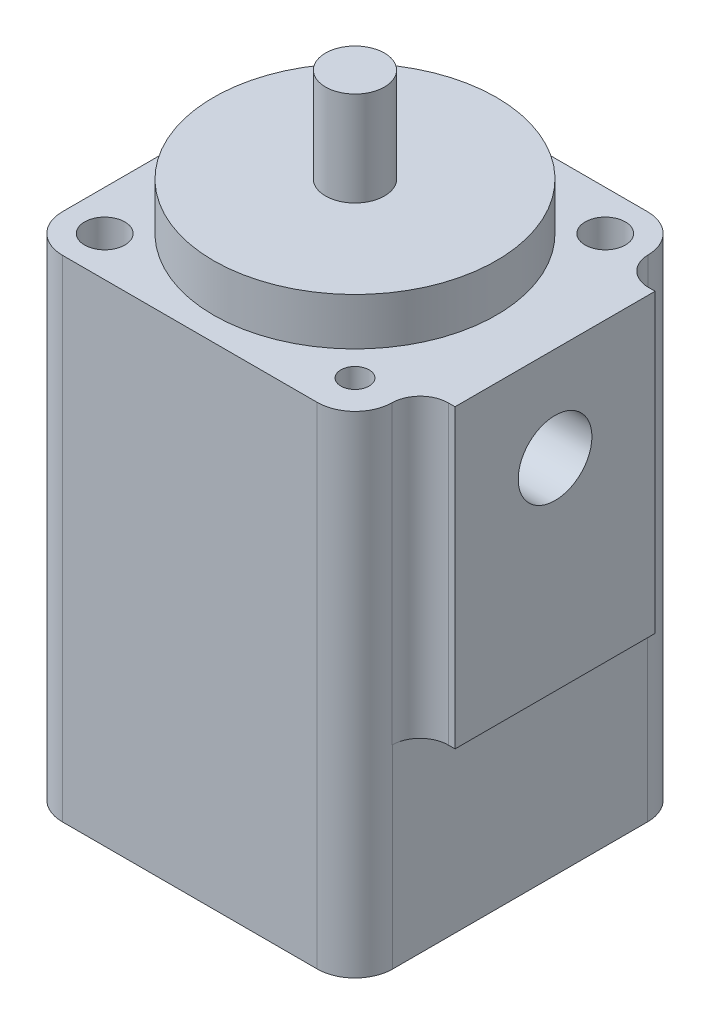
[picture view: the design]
ISO-10303-21;
HEADER;
FILE_DESCRIPTION(('STEP AP214'),'2;1');
FILE_NAME('part.step','',(''),(''),'','','');
FILE_SCHEMA(('AUTOMOTIVE_DESIGN { 1 0 10303 214 1 1 1 1 }'));
ENDSEC;
DATA;
#1=APPLICATION_CONTEXT('core data for automotive mechanical design processes');
#2=APPLICATION_PROTOCOL_DEFINITION('international standard','automotive_design',2000,#1);
#3=PRODUCT_CONTEXT('',#1,'mechanical');
#4=PRODUCT('Part','Part','',(#3));
#5=PRODUCT_RELATED_PRODUCT_CATEGORY('part','',(#4));
#6=PRODUCT_DEFINITION_FORMATION('','',#4);
#7=PRODUCT_DEFINITION_CONTEXT('part definition',#1,'design');
#8=PRODUCT_DEFINITION('design','',#6,#7);
#9=PRODUCT_DEFINITION_SHAPE('','',#8);
#10=(LENGTH_UNIT() NAMED_UNIT(*) SI_UNIT(.MILLI.,.METRE.));
#11=(NAMED_UNIT(*) PLANE_ANGLE_UNIT() SI_UNIT($,.RADIAN.));
#12=(NAMED_UNIT(*) SI_UNIT($,.STERADIAN.) SOLID_ANGLE_UNIT());
#13=UNCERTAINTY_MEASURE_WITH_UNIT(LENGTH_MEASURE(1.E-05),#10,'distance_accuracy_value','');
#14=(GEOMETRIC_REPRESENTATION_CONTEXT(3) GLOBAL_UNCERTAINTY_ASSIGNED_CONTEXT((#13)) GLOBAL_UNIT_ASSIGNED_CONTEXT((#10,
#11,#12)) REPRESENTATION_CONTEXT('',''));
#15=CARTESIAN_POINT('',(0.,0.,0.));
#16=DIRECTION('',(0.,0.,1.));
#17=DIRECTION('',(1.,0.,0.));
#18=AXIS2_PLACEMENT_3D('',#15,#16,#17);
#19=CARTESIAN_POINT('',(0.,85.09,0.));
#20=DIRECTION('',(0.,-1.,0.));
#21=DIRECTION('',(0.,0.,-1.));
#22=AXIS2_PLACEMENT_3D('',#19,#20,#21);
#23=PLANE('',#22);
#24=CARTESIAN_POINT('',(0.,85.09,0.));
#25=DIRECTION('',(0.,-1.,0.));
#26=DIRECTION('',(0.,0.,-1.));
#27=AXIS2_PLACEMENT_3D('',#24,#25,#26);
#28=CIRCLE('',#27,3.9624);
#29=CARTESIAN_POINT('',(0.,85.09,-3.9624));
#30=VERTEX_POINT('',#29);
#31=EDGE_CURVE('E13',#30,#30,#28,.T.);
#32=ORIENTED_EDGE('',*,*,#31,.F.);
#33=EDGE_LOOP('',(#32));
#34=FACE_BOUND('',#33,.T.);
#35=ADVANCED_FACE('F58',(#34),#23,.F.);
#36=CARTESIAN_POINT('',(0.,0.,0.));
#37=DIRECTION('',(0.,-1.,0.));
#38=DIRECTION('',(0.,0.,-1.));
#39=AXIS2_PLACEMENT_3D('',#36,#37,#38);
#40=CYLINDRICAL_SURFACE('',#39,3.9624);
#41=CARTESIAN_POINT('',(0.,46.99,0.));
#42=DIRECTION('',(0.,-1.,0.));
#43=DIRECTION('',(0.,0.,-1.));
#44=AXIS2_PLACEMENT_3D('',#41,#42,#43);
#45=CIRCLE('',#44,3.9624);
#46=CARTESIAN_POINT('',(0.,46.99,-3.9624));
#47=VERTEX_POINT('',#46);
#48=EDGE_CURVE('E64',#47,#47,#45,.T.);
#49=ORIENTED_EDGE('',*,*,#48,.F.);
#50=EDGE_LOOP('',(#49));
#51=FACE_BOUND('',#50,.T.);
#52=ORIENTED_EDGE('',*,*,#31,.T.);
#53=EDGE_LOOP('',(#52));
#54=FACE_BOUND('',#53,.T.);
#55=ADVANCED_FACE('F72',(#51,#54),#40,.T.);
#56=CARTESIAN_POINT('',(0.,46.99,0.));
#57=DIRECTION('',(0.,1.,0.));
#58=DIRECTION('',(0.,0.,1.));
#59=AXIS2_PLACEMENT_3D('',#56,#57,#58);
#60=PLANE('',#59);
#61=ORIENTED_EDGE('',*,*,#48,.T.);
#62=EDGE_LOOP('',(#61));
#63=FACE_BOUND('',#62,.T.);
#64=ADVANCED_FACE('F70',(#63),#60,.F.);
#65=CLOSED_SHELL('',(#35,#55,#64));
#66=MANIFOLD_SOLID_BREP('B2',#65);
#67=CARTESIAN_POINT('',(22.225,66.04,-22.225));
#68=DIRECTION('',(0.,-1.,0.));
#69=DIRECTION('',(0.,0.,-1.));
#70=AXIS2_PLACEMENT_3D('',#67,#68,#69);
#71=PLANE('',#70);
#72=CARTESIAN_POINT('',(16.8402,66.04,-16.8402));
#73=DIRECTION('',(0.,1.,0.));
#74=DIRECTION('',(0.,0.,1.));
#75=AXIS2_PLACEMENT_3D('',#72,#73,#74);
#76=CIRCLE('',#75,2.70509999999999);
#77=CARTESIAN_POINT('',(16.8402,66.04,-14.1351));
#78=VERTEX_POINT('',#77);
#79=EDGE_CURVE('E302',#78,#78,#76,.T.);
#80=ORIENTED_EDGE('',*,*,#79,.F.);
#81=EDGE_LOOP('',(#80));
#82=FACE_BOUND('',#81,.T.);
#83=CARTESIAN_POINT('',(-16.8402,66.04,-16.8402));
#84=DIRECTION('',(0.,1.,0.));
#85=DIRECTION('',(0.,0.,1.));
#86=AXIS2_PLACEMENT_3D('',#83,#84,#85);
#87=CIRCLE('',#86,1.89864999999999);
#88=CARTESIAN_POINT('',(-16.8402,66.04,-14.94155));
#89=VERTEX_POINT('',#88);
#90=EDGE_CURVE('E314',#89,#89,#87,.T.);
#91=ORIENTED_EDGE('',*,*,#90,.F.);
#92=EDGE_LOOP('',(#91));
#93=FACE_BOUND('',#92,.T.);
#94=DIRECTION('',(-1.,0.,0.));
#95=VECTOR('',#94,1.);
#96=CARTESIAN_POINT('',(-22.225,66.04,-22.225));
#97=LINE('',#96,#95);
#98=CARTESIAN_POINT('',(17.145,66.04,-22.225));
#99=VERTEX_POINT('',#98);
#100=CARTESIAN_POINT('',(-17.145,66.04,-22.225));
#101=VERTEX_POINT('',#100);
#102=EDGE_CURVE('E364',#99,#101,#97,.T.);
#103=ORIENTED_EDGE('',*,*,#102,.T.);
#104=CARTESIAN_POINT('',(-17.145,66.04,-17.145));
#105=DIRECTION('',(0.,-1.,0.));
#106=DIRECTION('',(0.,0.,-1.));
#107=AXIS2_PLACEMENT_3D('',#104,#105,#106);
#108=CIRCLE('',#107,5.08);
#109=CARTESIAN_POINT('',(-22.225,66.04,-17.145));
#110=VERTEX_POINT('',#109);
#111=EDGE_CURVE('E412',#101,#110,#108,.F.);
#112=ORIENTED_EDGE('',*,*,#111,.T.);
#113=DIRECTION('',(0.,0.,1.));
#114=VECTOR('',#113,1.);
#115=CARTESIAN_POINT('',(-22.225,66.04,22.225));
#116=LINE('',#115,#114);
#117=CARTESIAN_POINT('',(-22.225,66.04,17.145));
#118=VERTEX_POINT('',#117);
#119=EDGE_CURVE('E367',#110,#118,#116,.T.);
#120=ORIENTED_EDGE('',*,*,#119,.T.);
#121=CARTESIAN_POINT('',(-17.145,66.04,17.145));
#122=DIRECTION('',(0.,-1.,0.));
#123=DIRECTION('',(0.,0.,-1.));
#124=AXIS2_PLACEMENT_3D('',#121,#122,#123);
#125=CIRCLE('',#124,5.08);
#126=CARTESIAN_POINT('',(-17.145,66.04,22.225));
#127=VERTEX_POINT('',#126);
#128=EDGE_CURVE('E410',#118,#127,#125,.F.);
#129=ORIENTED_EDGE('',*,*,#128,.T.);
#130=DIRECTION('',(1.,0.,0.));
#131=VECTOR('',#130,1.);
#132=CARTESIAN_POINT('',(-22.225,66.04,22.225));
#133=LINE('',#132,#131);
#134=CARTESIAN_POINT('',(17.145,66.04,22.225));
#135=VERTEX_POINT('',#134);
#136=EDGE_CURVE('E371',#127,#135,#133,.T.);
#137=ORIENTED_EDGE('',*,*,#136,.T.);
#138=CARTESIAN_POINT('',(17.145,66.04,17.145));
#139=DIRECTION('',(0.,-1.,0.));
#140=DIRECTION('',(0.,0.,-1.));
#141=AXIS2_PLACEMENT_3D('',#138,#139,#140);
#142=CIRCLE('',#141,5.08);
#143=CARTESIAN_POINT('',(22.2244816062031,66.04,17.2175714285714));
#144=VERTEX_POINT('',#143);
#145=EDGE_CURVE('E405',#135,#144,#142,.F.);
#146=ORIENTED_EDGE('',*,*,#145,.T.);
#147=CARTESIAN_POINT('',(26.0340928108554,66.04,17.272));
#148=DIRECTION('',(0.,-1.,0.));
#149=DIRECTION('',(0.,0.,-1.));
#150=AXIS2_PLACEMENT_3D('',#147,#148,#149);
#151=CIRCLE('',#150,3.81);
#152=CARTESIAN_POINT('',(26.0340928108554,66.04,13.462));
#153=VERTEX_POINT('',#152);
#154=EDGE_CURVE('E441',#144,#153,#151,.T.);
#155=ORIENTED_EDGE('',*,*,#154,.T.);
#156=DIRECTION('',(1.,0.,0.));
#157=VECTOR('',#156,1.);
#158=CARTESIAN_POINT('',(26.924,66.04,13.462));
#159=LINE('',#158,#157);
#160=CARTESIAN_POINT('',(26.924,66.04,13.462));
#161=VERTEX_POINT('',#160);
#162=EDGE_CURVE('E343',#153,#161,#159,.T.);
#163=ORIENTED_EDGE('',*,*,#162,.T.);
#164=DIRECTION('',(0.,0.,-1.));
#165=VECTOR('',#164,1.);
#166=CARTESIAN_POINT('',(26.924,66.04,-13.462));
#167=LINE('',#166,#165);
#168=CARTESIAN_POINT('',(26.924,66.04,-13.462));
#169=VERTEX_POINT('',#168);
#170=EDGE_CURVE('E345',#161,#169,#167,.T.);
#171=ORIENTED_EDGE('',*,*,#170,.T.);
#172=DIRECTION('',(-1.,0.,0.));
#173=VECTOR('',#172,1.);
#174=CARTESIAN_POINT('',(22.225,66.04,-13.462));
#175=LINE('',#174,#173);
#176=CARTESIAN_POINT('',(26.0340928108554,66.04,-13.462));
#177=VERTEX_POINT('',#176);
#178=EDGE_CURVE('E334',#169,#177,#175,.T.);
#179=ORIENTED_EDGE('',*,*,#178,.T.);
#180=CARTESIAN_POINT('',(26.0340928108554,66.04,-17.272));
#181=DIRECTION('',(0.,-1.,0.));
#182=DIRECTION('',(0.,0.,-1.));
#183=AXIS2_PLACEMENT_3D('',#180,#181,#182);
#184=CIRCLE('',#183,3.81);
#185=CARTESIAN_POINT('',(22.2244816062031,66.04,-17.2175714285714));
#186=VERTEX_POINT('',#185);
#187=EDGE_CURVE('E445',#177,#186,#184,.T.);
#188=ORIENTED_EDGE('',*,*,#187,.T.);
#189=CARTESIAN_POINT('',(17.145,66.04,-17.145));
#190=DIRECTION('',(0.,-1.,0.));
#191=DIRECTION('',(0.,0.,-1.));
#192=AXIS2_PLACEMENT_3D('',#189,#190,#191);
#193=CIRCLE('',#192,5.08);
#194=EDGE_CURVE('E408',#186,#99,#193,.F.);
#195=ORIENTED_EDGE('',*,*,#194,.T.);
#196=EDGE_LOOP('',(#103,#112,#120,#129,#137,#146,#155,#163,#171,#179,#188,#195));
#197=FACE_BOUND('',#196,.T.);
#198=CARTESIAN_POINT('',(0.,66.04,0.));
#199=DIRECTION('',(0.,-1.,0.));
#200=DIRECTION('',(0.,0.,-1.));
#201=AXIS2_PLACEMENT_3D('',#198,#199,#200);
#202=CIRCLE('',#201,19.0373);
#203=CARTESIAN_POINT('',(0.,66.04,-19.0373));
#204=VERTEX_POINT('',#203);
#205=EDGE_CURVE('E374',#204,#204,#202,.F.);
#206=ORIENTED_EDGE('',*,*,#205,.F.);
#207=EDGE_LOOP('',(#206));
#208=FACE_BOUND('',#207,.T.);
#209=CARTESIAN_POINT('',(16.8402,66.04,16.8402));
#210=DIRECTION('',(0.,1.,0.));
#211=DIRECTION('',(0.,0.,1.));
#212=AXIS2_PLACEMENT_3D('',#209,#210,#211);
#213=CIRCLE('',#212,1.89864999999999);
#214=CARTESIAN_POINT('',(16.8402,66.04,18.73885));
#215=VERTEX_POINT('',#214);
#216=EDGE_CURVE('E320',#215,#215,#213,.T.);
#217=ORIENTED_EDGE('',*,*,#216,.F.);
#218=EDGE_LOOP('',(#217));
#219=FACE_BOUND('',#218,.T.);
#220=CARTESIAN_POINT('',(-16.8402,66.04,16.8402));
#221=DIRECTION('',(0.,1.,0.));
#222=DIRECTION('',(0.,0.,1.));
#223=AXIS2_PLACEMENT_3D('',#220,#221,#222);
#224=CIRCLE('',#223,2.70509999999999);
#225=CARTESIAN_POINT('',(-16.8402,66.04,19.5453));
#226=VERTEX_POINT('',#225);
#227=EDGE_CURVE('E308',#226,#226,#224,.T.);
#228=ORIENTED_EDGE('',*,*,#227,.F.);
#229=EDGE_LOOP('',(#228));
#230=FACE_BOUND('',#229,.T.);
#231=ADVANCED_FACE('F104',(#82,#93,#197,#208,#219,#230),#71,.F.);
#232=CARTESIAN_POINT('',(22.225,0.,-22.225));
#233=DIRECTION('',(0.,-1.,0.));
#234=DIRECTION('',(0.,0.,-1.));
#235=AXIS2_PLACEMENT_3D('',#232,#233,#234);
#236=PLANE('',#235);
#237=CARTESIAN_POINT('',(0.,0.,-9.52500000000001));
#238=DIRECTION('',(0.,-1.,0.));
#239=DIRECTION('',(0.,0.,-1.));
#240=AXIS2_PLACEMENT_3D('',#237,#238,#239);
#241=CIRCLE('',#240,10.5);
#242=CARTESIAN_POINT('',(-4.41863949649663,0.,0.));
#243=VERTEX_POINT('',#242);
#244=CARTESIAN_POINT('',(4.41863949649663,0.,0.));
#245=VERTEX_POINT('',#244);
#246=EDGE_CURVE('E268',#243,#245,#241,.T.);
#247=ORIENTED_EDGE('',*,*,#246,.F.);
#248=CARTESIAN_POINT('',(0.,0.,9.52500000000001));
#249=DIRECTION('',(0.,-1.,0.));
#250=DIRECTION('',(0.,0.,-1.));
#251=AXIS2_PLACEMENT_3D('',#248,#249,#250);
#252=CIRCLE('',#251,10.5);
#253=EDGE_CURVE('E299',#245,#243,#252,.T.);
#254=ORIENTED_EDGE('',*,*,#253,.F.);
#255=EDGE_LOOP('',(#247,#254));
#256=FACE_BOUND('',#255,.T.);
#257=CARTESIAN_POINT('',(16.8402,0.,-16.8402));
#258=DIRECTION('',(0.,1.,0.));
#259=DIRECTION('',(0.,0.,1.));
#260=AXIS2_PLACEMENT_3D('',#257,#258,#259);
#261=CIRCLE('',#260,2.70509999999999);
#262=CARTESIAN_POINT('',(16.8402,0.,-14.1351));
#263=VERTEX_POINT('',#262);
#264=EDGE_CURVE('E305',#263,#263,#261,.T.);
#265=ORIENTED_EDGE('',*,*,#264,.T.);
#266=EDGE_LOOP('',(#265));
#267=FACE_BOUND('',#266,.T.);
#268=CARTESIAN_POINT('',(-16.8402,0.,16.8402));
#269=DIRECTION('',(0.,1.,0.));
#270=DIRECTION('',(0.,0.,1.));
#271=AXIS2_PLACEMENT_3D('',#268,#269,#270);
#272=CIRCLE('',#271,2.70509999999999);
#273=CARTESIAN_POINT('',(-16.8402,0.,19.5453));
#274=VERTEX_POINT('',#273);
#275=EDGE_CURVE('E311',#274,#274,#272,.T.);
#276=ORIENTED_EDGE('',*,*,#275,.T.);
#277=EDGE_LOOP('',(#276));
#278=FACE_BOUND('',#277,.T.);
#279=CARTESIAN_POINT('',(-16.8402,0.,-16.8402));
#280=DIRECTION('',(0.,1.,0.));
#281=DIRECTION('',(0.,0.,1.));
#282=AXIS2_PLACEMENT_3D('',#279,#280,#281);
#283=CIRCLE('',#282,1.89864999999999);
#284=CARTESIAN_POINT('',(-16.8402,0.,-14.94155));
#285=VERTEX_POINT('',#284);
#286=EDGE_CURVE('E317',#285,#285,#283,.T.);
#287=ORIENTED_EDGE('',*,*,#286,.T.);
#288=EDGE_LOOP('',(#287));
#289=FACE_BOUND('',#288,.T.);
#290=DIRECTION('',(0.,0.,1.));
#291=VECTOR('',#290,1.);
#292=CARTESIAN_POINT('',(-22.225,0.,22.225));
#293=LINE('',#292,#291);
#294=CARTESIAN_POINT('',(-22.225,0.,-17.145));
#295=VERTEX_POINT('',#294);
#296=CARTESIAN_POINT('',(-22.225,0.,17.145));
#297=VERTEX_POINT('',#296);
#298=EDGE_CURVE('E380',#295,#297,#293,.T.);
#299=ORIENTED_EDGE('',*,*,#298,.F.);
#300=CARTESIAN_POINT('',(-17.145,0.,-17.145));
#301=DIRECTION('',(0.,-1.,0.));
#302=DIRECTION('',(0.,0.,-1.));
#303=AXIS2_PLACEMENT_3D('',#300,#301,#302);
#304=CIRCLE('',#303,5.08);
#305=CARTESIAN_POINT('',(-17.145,0.,-22.225));
#306=VERTEX_POINT('',#305);
#307=EDGE_CURVE('E398',#295,#306,#304,.T.);
#308=ORIENTED_EDGE('',*,*,#307,.T.);
#309=DIRECTION('',(-1.,0.,0.));
#310=VECTOR('',#309,1.);
#311=CARTESIAN_POINT('',(-22.225,0.,-22.225));
#312=LINE('',#311,#310);
#313=CARTESIAN_POINT('',(17.145,0.,-22.225));
#314=VERTEX_POINT('',#313);
#315=EDGE_CURVE('E377',#314,#306,#312,.T.);
#316=ORIENTED_EDGE('',*,*,#315,.F.);
#317=CARTESIAN_POINT('',(17.145,0.,-17.145));
#318=DIRECTION('',(0.,-1.,0.));
#319=DIRECTION('',(0.,0.,-1.));
#320=AXIS2_PLACEMENT_3D('',#317,#318,#319);
#321=CIRCLE('',#320,5.08);
#322=CARTESIAN_POINT('',(22.225,0.,-17.145));
#323=VERTEX_POINT('',#322);
#324=EDGE_CURVE('E394',#314,#323,#321,.T.);
#325=ORIENTED_EDGE('',*,*,#324,.T.);
#326=DIRECTION('',(0.,0.,-1.));
#327=VECTOR('',#326,1.);
#328=CARTESIAN_POINT('',(22.225,0.,22.225));
#329=LINE('',#328,#327);
#330=CARTESIAN_POINT('',(22.225,0.,17.145));
#331=VERTEX_POINT('',#330);
#332=EDGE_CURVE('E363',#331,#323,#329,.T.);
#333=ORIENTED_EDGE('',*,*,#332,.F.);
#334=CARTESIAN_POINT('',(17.145,0.,17.145));
#335=DIRECTION('',(0.,-1.,0.));
#336=DIRECTION('',(0.,0.,-1.));
#337=AXIS2_PLACEMENT_3D('',#334,#335,#336);
#338=CIRCLE('',#337,5.08);
#339=CARTESIAN_POINT('',(17.145,0.,22.225));
#340=VERTEX_POINT('',#339);
#341=EDGE_CURVE('E392',#331,#340,#338,.T.);
#342=ORIENTED_EDGE('',*,*,#341,.T.);
#343=DIRECTION('',(1.,0.,0.));
#344=VECTOR('',#343,1.);
#345=CARTESIAN_POINT('',(-22.225,0.,22.225));
#346=LINE('',#345,#344);
#347=CARTESIAN_POINT('',(-17.145,0.,22.225));
#348=VERTEX_POINT('',#347);
#349=EDGE_CURVE('E368',#348,#340,#346,.T.);
#350=ORIENTED_EDGE('',*,*,#349,.F.);
#351=CARTESIAN_POINT('',(-17.145,0.,17.145));
#352=DIRECTION('',(0.,-1.,0.));
#353=DIRECTION('',(0.,0.,-1.));
#354=AXIS2_PLACEMENT_3D('',#351,#352,#353);
#355=CIRCLE('',#354,5.08);
#356=EDGE_CURVE('E396',#348,#297,#355,.T.);
#357=ORIENTED_EDGE('',*,*,#356,.T.);
#358=EDGE_LOOP('',(#299,#308,#316,#325,#333,#342,#350,#357));
#359=FACE_BOUND('',#358,.T.);
#360=CARTESIAN_POINT('',(16.8402,0.,16.8402));
#361=DIRECTION('',(0.,1.,0.));
#362=DIRECTION('',(0.,0.,1.));
#363=AXIS2_PLACEMENT_3D('',#360,#361,#362);
#364=CIRCLE('',#363,1.89864999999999);
#365=CARTESIAN_POINT('',(16.8402,0.,18.73885));
#366=VERTEX_POINT('',#365);
#367=EDGE_CURVE('E323',#366,#366,#364,.T.);
#368=ORIENTED_EDGE('',*,*,#367,.T.);
#369=EDGE_LOOP('',(#368));
#370=FACE_BOUND('',#369,.T.);
#371=ADVANCED_FACE('F505',(#256,#267,#278,#289,#359,#370),#236,.T.);
#372=CARTESIAN_POINT('',(22.225,66.04,22.225));
#373=DIRECTION('',(-1.,0.,0.));
#374=DIRECTION('',(0.,0.,1.));
#375=AXIS2_PLACEMENT_3D('',#372,#373,#374);
#376=PLANE('',#375);
#377=DIRECTION('',(0.,0.,1.));
#378=VECTOR('',#377,1.);
#379=CARTESIAN_POINT('',(22.225,26.162,-13.462));
#380=LINE('',#379,#378);
#381=CARTESIAN_POINT('',(22.225,26.162,-17.145));
#382=VERTEX_POINT('',#381);
#383=CARTESIAN_POINT('',(22.225,26.162,17.145));
#384=VERTEX_POINT('',#383);
#385=EDGE_CURVE('E331',#382,#384,#380,.T.);
#386=ORIENTED_EDGE('',*,*,#385,.T.);
#387=DIRECTION('',(0.,-1.,0.));
#388=VECTOR('',#387,1.);
#389=CARTESIAN_POINT('',(22.225,66.04,17.145));
#390=LINE('',#389,#388);
#391=EDGE_CURVE('E419',#384,#331,#390,.T.);
#392=ORIENTED_EDGE('',*,*,#391,.T.);
#393=ORIENTED_EDGE('',*,*,#332,.T.);
#394=DIRECTION('',(0.,-1.,0.));
#395=VECTOR('',#394,1.);
#396=CARTESIAN_POINT('',(22.225,66.04,-17.145));
#397=LINE('',#396,#395);
#398=EDGE_CURVE('E421',#323,#382,#397,.F.);
#399=ORIENTED_EDGE('',*,*,#398,.T.);
#400=EDGE_LOOP('',(#386,#392,#393,#399));
#401=FACE_BOUND('',#400,.T.);
#402=ADVANCED_FACE('F511',(#401),#376,.F.);
#403=CARTESIAN_POINT('',(-22.225,66.04,-22.225));
#404=DIRECTION('',(0.,0.,1.));
#405=DIRECTION('',(1.,0.,0.));
#406=AXIS2_PLACEMENT_3D('',#403,#404,#405);
#407=PLANE('',#406);
#408=ORIENTED_EDGE('',*,*,#315,.T.);
#409=DIRECTION('',(0.,-1.,0.));
#410=VECTOR('',#409,1.);
#411=CARTESIAN_POINT('',(-17.145,66.04,-22.225));
#412=LINE('',#411,#410);
#413=EDGE_CURVE('E403',#306,#101,#412,.F.);
#414=ORIENTED_EDGE('',*,*,#413,.T.);
#415=ORIENTED_EDGE('',*,*,#102,.F.);
#416=DIRECTION('',(0.,-1.,0.));
#417=VECTOR('',#416,1.);
#418=CARTESIAN_POINT('',(17.145,66.04,-22.225));
#419=LINE('',#418,#417);
#420=EDGE_CURVE('E400',#99,#314,#419,.T.);
#421=ORIENTED_EDGE('',*,*,#420,.T.);
#422=EDGE_LOOP('',(#408,#414,#415,#421));
#423=FACE_BOUND('',#422,.T.);
#424=ADVANCED_FACE('F526',(#423),#407,.F.);
#425=CARTESIAN_POINT('',(-22.225,66.04,22.225));
#426=DIRECTION('',(1.,0.,0.));
#427=DIRECTION('',(0.,0.,-1.));
#428=AXIS2_PLACEMENT_3D('',#425,#426,#427);
#429=PLANE('',#428);
#430=ORIENTED_EDGE('',*,*,#119,.F.);
#431=DIRECTION('',(0.,-1.,0.));
#432=VECTOR('',#431,1.);
#433=CARTESIAN_POINT('',(-22.225,66.04,-17.145));
#434=LINE('',#433,#432);
#435=EDGE_CURVE('E389',#110,#295,#434,.T.);
#436=ORIENTED_EDGE('',*,*,#435,.T.);
#437=ORIENTED_EDGE('',*,*,#298,.T.);
#438=DIRECTION('',(0.,-1.,0.));
#439=VECTOR('',#438,1.);
#440=CARTESIAN_POINT('',(-22.225,66.04,17.145));
#441=LINE('',#440,#439);
#442=EDGE_CURVE('E387',#297,#118,#441,.F.);
#443=ORIENTED_EDGE('',*,*,#442,.T.);
#444=EDGE_LOOP('',(#430,#436,#437,#443));
#445=FACE_BOUND('',#444,.T.);
#446=ADVANCED_FACE('F522',(#445),#429,.F.);
#447=CARTESIAN_POINT('',(-22.225,66.04,22.225));
#448=DIRECTION('',(0.,0.,-1.));
#449=DIRECTION('',(-1.,0.,0.));
#450=AXIS2_PLACEMENT_3D('',#447,#448,#449);
#451=PLANE('',#450);
#452=ORIENTED_EDGE('',*,*,#136,.F.);
#453=DIRECTION('',(0.,-1.,0.));
#454=VECTOR('',#453,1.);
#455=CARTESIAN_POINT('',(-17.145,66.04,22.225));
#456=LINE('',#455,#454);
#457=EDGE_CURVE('E416',#127,#348,#456,.T.);
#458=ORIENTED_EDGE('',*,*,#457,.T.);
#459=ORIENTED_EDGE('',*,*,#349,.T.);
#460=DIRECTION('',(0.,-1.,0.));
#461=VECTOR('',#460,1.);
#462=CARTESIAN_POINT('',(17.145,66.04,22.225));
#463=LINE('',#462,#461);
#464=EDGE_CURVE('E414',#340,#135,#463,.F.);
#465=ORIENTED_EDGE('',*,*,#464,.T.);
#466=EDGE_LOOP('',(#452,#458,#459,#465));
#467=FACE_BOUND('',#466,.T.);
#468=ADVANCED_FACE('F519',(#467),#451,.F.);
#469=CARTESIAN_POINT('',(0.,72.39,0.));
#470=DIRECTION('',(0.,-1.,0.));
#471=DIRECTION('',(0.,0.,-1.));
#472=AXIS2_PLACEMENT_3D('',#469,#470,#471);
#473=CYLINDRICAL_SURFACE('',#472,19.0373);
#474=CARTESIAN_POINT('',(0.,72.39,0.));
#475=DIRECTION('',(0.,1.,0.));
#476=DIRECTION('',(0.,0.,1.));
#477=AXIS2_PLACEMENT_3D('',#474,#475,#476);
#478=CIRCLE('',#477,19.0373);
#479=CARTESIAN_POINT('',(0.,72.39,19.0373));
#480=VERTEX_POINT('',#479);
#481=EDGE_CURVE('E358',#480,#480,#478,.T.);
#482=ORIENTED_EDGE('',*,*,#481,.F.);
#483=EDGE_LOOP('',(#482));
#484=FACE_BOUND('',#483,.T.);
#485=ORIENTED_EDGE('',*,*,#205,.T.);
#486=EDGE_LOOP('',(#485));
#487=FACE_BOUND('',#486,.T.);
#488=ADVANCED_FACE('F517',(#484,#487),#473,.T.);
#489=CARTESIAN_POINT('',(0.,72.39,0.));
#490=DIRECTION('',(0.,1.,0.));
#491=DIRECTION('',(0.,0.,1.));
#492=AXIS2_PLACEMENT_3D('',#489,#490,#491);
#493=PLANE('',#492);
#494=CARTESIAN_POINT('',(0.,72.39,0.));
#495=DIRECTION('',(0.,1.,0.));
#496=DIRECTION('',(0.,0.,1.));
#497=AXIS2_PLACEMENT_3D('',#494,#495,#496);
#498=CIRCLE('',#497,3.96875);
#499=CARTESIAN_POINT('',(0.,72.39,3.96875));
#500=VERTEX_POINT('',#499);
#501=EDGE_CURVE('E352',#500,#500,#498,.T.);
#502=ORIENTED_EDGE('',*,*,#501,.F.);
#503=EDGE_LOOP('',(#502));
#504=FACE_BOUND('',#503,.T.);
#505=ORIENTED_EDGE('',*,*,#481,.T.);
#506=EDGE_LOOP('',(#505));
#507=FACE_BOUND('',#506,.T.);
#508=ADVANCED_FACE('F502',(#504,#507),#493,.T.);
#509=CARTESIAN_POINT('',(0.,34.29,0.));
#510=DIRECTION('',(0.,1.,0.));
#511=DIRECTION('',(0.,0.,1.));
#512=AXIS2_PLACEMENT_3D('',#509,#510,#511);
#513=CYLINDRICAL_SURFACE('',#512,3.96875);
#514=DIRECTION('',(0.,1.,0.));
#515=VECTOR('',#514,1.);
#516=CARTESIAN_POINT('',(0.762,34.29,-3.89491111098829));
#517=LINE('',#516,#515);
#518=CARTESIAN_POINT('',(0.762,50.2679618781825,-3.89491111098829));
#519=VERTEX_POINT('',#518);
#520=CARTESIAN_POINT('',(0.762,56.4120381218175,-3.89491111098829));
#521=VERTEX_POINT('',#520);
#522=EDGE_CURVE('E455',#519,#521,#517,.T.);
#523=ORIENTED_EDGE('',*,*,#522,.T.);
#524=CARTESIAN_POINT('',(0.762,56.4120381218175,-3.89491111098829));
#525=CARTESIAN_POINT('',(0.872602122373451,56.4394920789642,-3.87326278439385));
#526=CARTESIAN_POINT('',(0.98086788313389,56.4719380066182,-3.84720182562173));
#527=CARTESIAN_POINT('',(1.19218803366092,56.5444070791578,-3.78704563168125));
#528=CARTESIAN_POINT('',(1.29525636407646,56.5844084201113,-3.75297344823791));
#529=CARTESIAN_POINT('',(1.49566621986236,56.6695055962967,-3.67768316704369));
#530=CARTESIAN_POINT('',(1.5930386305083,56.7145691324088,-3.63650956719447));
#531=CARTESIAN_POINT('',(1.78287873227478,56.808231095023,-3.54729779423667));
#532=CARTESIAN_POINT('',(1.87534246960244,56.8568322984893,-3.4992541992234));
#533=CARTESIAN_POINT('',(2.14346593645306,57.0045588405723,-3.34643132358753));
#534=CARTESIAN_POINT('',(2.31214160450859,57.1066517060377,-3.2320830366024));
#535=CARTESIAN_POINT('',(2.63072429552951,57.3102094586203,-2.97855163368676));
#536=CARTESIAN_POINT('',(2.78058879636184,57.4116724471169,-2.83931391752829));
#537=CARTESIAN_POINT('',(3.06070716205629,57.6078620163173,-2.5349926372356));
#538=CARTESIAN_POINT('',(3.19076478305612,57.7025168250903,-2.36967981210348));
#539=CARTESIAN_POINT('',(3.4256245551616,57.8771294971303,-2.01521458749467));
#540=CARTESIAN_POINT('',(3.53047206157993,57.9571136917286,-1.82610594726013));
#541=CARTESIAN_POINT('',(3.69375347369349,58.0832505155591,-1.46266618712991));
#542=CARTESIAN_POINT('',(3.75714272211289,58.1329001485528,-1.2917896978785));
#543=CARTESIAN_POINT('',(3.86044559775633,58.2142994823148,-0.938962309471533));
#544=CARTESIAN_POINT('',(3.90037223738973,58.2460591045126,-0.757017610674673));
#545=CARTESIAN_POINT('',(3.95439235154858,58.2891133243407,-0.386039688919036));
#546=CARTESIAN_POINT('',(3.96836910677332,58.3003154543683,-0.196978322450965));
#547=CARTESIAN_POINT('',(3.96911526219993,58.3009120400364,0.181225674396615));
#548=CARTESIAN_POINT('',(3.95588783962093,58.2903090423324,0.370368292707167));
#549=CARTESIAN_POINT('',(3.9051423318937,58.2498577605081,0.728854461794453));
#550=CARTESIAN_POINT('',(3.86946961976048,58.2214722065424,0.898634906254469));
#551=CARTESIAN_POINT('',(3.7775713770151,58.1489525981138,1.22896239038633));
#552=CARTESIAN_POINT('',(3.72134037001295,58.1048143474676,1.38950695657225));
#553=CARTESIAN_POINT('',(3.5858484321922,57.999733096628,1.71034193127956));
#554=CARTESIAN_POINT('',(3.50516429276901,57.9377694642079,1.86968958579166));
#555=CARTESIAN_POINT('',(3.32589301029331,57.802608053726,2.17265656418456));
#556=CARTESIAN_POINT('',(3.22730049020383,57.7294069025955,2.31627114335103));
#557=CARTESIAN_POINT('',(2.99373860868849,57.5603667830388,2.61361058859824));
#558=CARTESIAN_POINT('',(2.8554280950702,57.4629059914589,2.76377649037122));
#559=CARTESIAN_POINT('',(2.5590236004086,57.2634213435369,3.04032718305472));
#560=CARTESIAN_POINT('',(2.4008891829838,57.1613884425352,3.1666620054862));
#561=CARTESIAN_POINT('',(2.15139891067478,57.0116523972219,3.33651112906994));
#562=CARTESIAN_POINT('',(2.0670390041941,56.9627389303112,3.38944204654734));
#563=CARTESIAN_POINT('',(1.89374016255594,56.8667273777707,3.48923040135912));
#564=CARTESIAN_POINT('',(1.80480006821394,56.8196297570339,3.53608629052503));
#565=CARTESIAN_POINT('',(1.62270487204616,56.7287679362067,3.62325141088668));
#566=CARTESIAN_POINT('',(1.52957009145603,56.684989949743,3.66358860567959));
#567=CARTESIAN_POINT('',(1.33867874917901,56.6021235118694,3.73756365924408));
#568=CARTESIAN_POINT('',(1.2409247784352,56.563032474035,3.77120521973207));
#569=CARTESIAN_POINT('',(1.07945788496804,56.5052356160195,3.81966782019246));
#570=CARTESIAN_POINT('',(1.01715104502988,56.4844810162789,3.8367444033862));
#571=CARTESIAN_POINT('',(0.890820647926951,56.4459151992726,3.86803010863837));
#572=CARTESIAN_POINT('',(0.826794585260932,56.428108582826,3.88223475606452));
#573=CARTESIAN_POINT('',(0.762,56.4120381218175,3.89491111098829));
#574=B_SPLINE_CURVE_WITH_KNOTS('',3,(#524,#525,#526,#527,#528,#529,#530,#531,#532,#533,#534,
#535,#536,#537,#538,#539,#540,#541,#542,#543,#544,#545,#546,#547,#548,#549,#550,#551,#552,#553,
#554,#555,#556,#557,#558,#559,#560,#561,#562,#563,#564,#565,#566,#567,#568,#569,#570,#571,#572,
#573),.UNSPECIFIED.,.F.,.F.,(4,2,2,2,2,2,2,2,2,2,2,2,2,2,2,2,2,2,2,2,2,2,2,2,4),(0.,
0.34745550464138,0.693923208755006,1.0382939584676,1.38293800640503,2.06432483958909,
2.7472252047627,3.4365040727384,4.12453342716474,4.68887944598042,5.25291218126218,
5.819475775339,6.38597320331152,6.91108033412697,7.4363274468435,8.00141087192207,
8.56666424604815,9.24299422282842,9.92072692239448,10.2533741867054,10.5861060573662,
10.9173703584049,11.2484510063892,11.451886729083,11.6556370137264),.UNSPECIFIED.);
#575=CARTESIAN_POINT('',(0.762,56.4120381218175,3.89491111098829));
#576=VERTEX_POINT('',#575);
#577=EDGE_CURVE('E56',#521,#576,#574,.T.);
#578=ORIENTED_EDGE('',*,*,#577,.T.);
#579=DIRECTION('',(0.,1.,0.));
#580=VECTOR('',#579,1.);
#581=CARTESIAN_POINT('',(0.762,34.29,3.89491111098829));
#582=LINE('',#581,#580);
#583=CARTESIAN_POINT('',(0.762,50.2679618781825,3.89491111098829));
#584=VERTEX_POINT('',#583);
#585=EDGE_CURVE('E117',#576,#584,#582,.F.);
#586=ORIENTED_EDGE('',*,*,#585,.T.);
#587=CARTESIAN_POINT('',(0.762,50.2679618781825,3.89491111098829));
#588=CARTESIAN_POINT('',(0.872602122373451,50.2405079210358,3.87326278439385));
#589=CARTESIAN_POINT('',(0.980867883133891,50.2080619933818,3.84720182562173));
#590=CARTESIAN_POINT('',(1.19218803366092,50.1355929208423,3.78704563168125));
#591=CARTESIAN_POINT('',(1.29525636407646,50.0955915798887,3.75297344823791));
#592=CARTESIAN_POINT('',(1.49566621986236,50.0104944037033,3.67768316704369));
#593=CARTESIAN_POINT('',(1.5930386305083,49.9654308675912,3.63650956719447));
#594=CARTESIAN_POINT('',(1.78287873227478,49.871768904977,3.54729779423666));
#595=CARTESIAN_POINT('',(1.87534246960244,49.8231677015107,3.4992541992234));
#596=CARTESIAN_POINT('',(2.14346593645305,49.6754411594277,3.34643132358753));
#597=CARTESIAN_POINT('',(2.31214160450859,49.5733482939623,3.2320830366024));
#598=CARTESIAN_POINT('',(2.63072429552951,49.3697905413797,2.97855163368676));
#599=CARTESIAN_POINT('',(2.78058879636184,49.2683275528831,2.8393139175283));
#600=CARTESIAN_POINT('',(3.06070716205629,49.0721379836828,2.5349926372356));
#601=CARTESIAN_POINT('',(3.19076478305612,48.9774831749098,2.36967981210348));
#602=CARTESIAN_POINT('',(3.4256245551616,48.8028705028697,2.01521458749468));
#603=CARTESIAN_POINT('',(3.53047206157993,48.7228863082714,1.82610594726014));
#604=CARTESIAN_POINT('',(3.69375347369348,48.5967494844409,1.46266618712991));
#605=CARTESIAN_POINT('',(3.75714272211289,48.5470998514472,1.29178969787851));
#606=CARTESIAN_POINT('',(3.86044559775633,48.4657005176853,0.938962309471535));
#607=CARTESIAN_POINT('',(3.90037223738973,48.4339408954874,0.757017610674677));
#608=CARTESIAN_POINT('',(3.95439235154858,48.3908866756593,0.386039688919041));
#609=CARTESIAN_POINT('',(3.96836910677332,48.3796845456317,0.19697832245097));
#610=CARTESIAN_POINT('',(3.96911526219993,48.3790879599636,-0.181225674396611));
#611=CARTESIAN_POINT('',(3.95588783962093,48.3896909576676,-0.370368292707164));
#612=CARTESIAN_POINT('',(3.9051423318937,48.4301422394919,-0.728854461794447));
#613=CARTESIAN_POINT('',(3.86946961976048,48.4585277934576,-0.89863490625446));
#614=CARTESIAN_POINT('',(3.7775713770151,48.5310474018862,-1.22896239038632));
#615=CARTESIAN_POINT('',(3.72134037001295,48.5751856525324,-1.38950695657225));
#616=CARTESIAN_POINT('',(3.58584843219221,48.680266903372,-1.71034193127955));
#617=CARTESIAN_POINT('',(3.50516429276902,48.7422305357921,-1.86968958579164));
#618=CARTESIAN_POINT('',(3.32589301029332,48.877391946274,-2.17265656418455));
#619=CARTESIAN_POINT('',(3.22730049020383,48.9505930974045,-2.31627114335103));
#620=CARTESIAN_POINT('',(2.99373860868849,49.1196332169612,-2.61361058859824));
#621=CARTESIAN_POINT('',(2.85542809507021,49.2170940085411,-2.76377649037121));
#622=CARTESIAN_POINT('',(2.55902360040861,49.4165786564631,-3.04032718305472));
#623=CARTESIAN_POINT('',(2.4008891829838,49.5186115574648,-3.16666200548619));
#624=CARTESIAN_POINT('',(2.15139891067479,49.6683476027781,-3.33651112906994));
#625=CARTESIAN_POINT('',(2.06703900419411,49.7172610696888,-3.38944204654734));
#626=CARTESIAN_POINT('',(1.89374016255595,49.8132726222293,-3.48923040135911));
#627=CARTESIAN_POINT('',(1.80480006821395,49.8603702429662,-3.53608629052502));
#628=CARTESIAN_POINT('',(1.62270487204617,49.9512320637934,-3.62325141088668));
#629=CARTESIAN_POINT('',(1.52957009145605,49.995010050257,-3.66358860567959));
#630=CARTESIAN_POINT('',(1.33867874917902,50.0778764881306,-3.73756365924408));
#631=CARTESIAN_POINT('',(1.2409247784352,50.116967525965,-3.77120521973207));
#632=CARTESIAN_POINT('',(1.07945788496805,50.1747643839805,-3.81966782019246));
#633=CARTESIAN_POINT('',(1.01715104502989,50.1955189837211,-3.8367444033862));
#634=CARTESIAN_POINT('',(0.890820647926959,50.2340848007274,-3.86803010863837));
#635=CARTESIAN_POINT('',(0.826794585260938,50.251891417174,-3.88223475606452));
#636=CARTESIAN_POINT('',(0.761999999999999,50.2679618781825,-3.89491111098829));
#637=B_SPLINE_CURVE_WITH_KNOTS('',3,(#587,#588,#589,#590,#591,#592,#593,#594,#595,#596,#597,
#598,#599,#600,#601,#602,#603,#604,#605,#606,#607,#608,#609,#610,#611,#612,#613,#614,#615,#616,
#617,#618,#619,#620,#621,#622,#623,#624,#625,#626,#627,#628,#629,#630,#631,#632,#633,#634,#635,
#636),.UNSPECIFIED.,.F.,.F.,(4,2,2,2,2,2,2,2,2,2,2,2,2,2,2,2,2,2,2,2,2,2,2,2,4),(0.,
0.347455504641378,0.693923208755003,1.03829395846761,1.38293800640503,2.06432483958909,
2.7472252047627,3.43650407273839,4.12453342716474,4.68887944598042,5.25291218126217,
5.819475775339,6.38597320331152,6.91108033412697,7.43632744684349,8.00141087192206,
8.56666424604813,9.24299422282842,9.92072692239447,10.2533741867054,10.5861060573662,
10.9173703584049,11.2484510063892,11.451886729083,11.6556370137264),.UNSPECIFIED.);
#638=EDGE_CURVE('E449',#584,#519,#637,.T.);
#639=ORIENTED_EDGE('',*,*,#638,.T.);
#640=EDGE_LOOP('',(#523,#578,#586,#639));
#641=FACE_BOUND('',#640,.T.);
#642=CARTESIAN_POINT('',(0.,34.29,0.));
#643=DIRECTION('',(0.,1.,0.));
#644=DIRECTION('',(0.,0.,1.));
#645=AXIS2_PLACEMENT_3D('',#642,#643,#644);
#646=CIRCLE('',#645,3.96875);
#647=CARTESIAN_POINT('',(0.,34.29,3.96875));
#648=VERTEX_POINT('',#647);
#649=EDGE_CURVE('E355',#648,#648,#646,.T.);
#650=ORIENTED_EDGE('',*,*,#649,.F.);
#651=EDGE_LOOP('',(#650));
#652=FACE_BOUND('',#651,.T.);
#653=ORIENTED_EDGE('',*,*,#501,.T.);
#654=EDGE_LOOP('',(#653));
#655=FACE_BOUND('',#654,.T.);
#656=ADVANCED_FACE('F456',(#641,#652,#655),#513,.F.);
#657=CARTESIAN_POINT('',(0.,34.29,0.));
#658=DIRECTION('',(0.,1.,0.));
#659=DIRECTION('',(0.,0.,1.));
#660=AXIS2_PLACEMENT_3D('',#657,#658,#659);
#661=PLANE('',#660);
#662=ORIENTED_EDGE('',*,*,#649,.T.);
#663=EDGE_LOOP('',(#662));
#664=FACE_BOUND('',#663,.T.);
#665=ADVANCED_FACE('F491',(#664),#661,.T.);
#666=CARTESIAN_POINT('',(-17.145,66.04,-17.145));
#667=DIRECTION('',(0.,-1.,0.));
#668=DIRECTION('',(0.,0.,-1.));
#669=AXIS2_PLACEMENT_3D('',#666,#667,#668);
#670=CYLINDRICAL_SURFACE('',#669,5.08);
#671=ORIENTED_EDGE('',*,*,#111,.F.);
#672=ORIENTED_EDGE('',*,*,#413,.F.);
#673=ORIENTED_EDGE('',*,*,#307,.F.);
#674=ORIENTED_EDGE('',*,*,#435,.F.);
#675=EDGE_LOOP('',(#671,#672,#673,#674));
#676=FACE_BOUND('',#675,.T.);
#677=ADVANCED_FACE('F493',(#676),#670,.T.);
#678=CARTESIAN_POINT('',(-17.145,66.04,17.145));
#679=DIRECTION('',(0.,-1.,0.));
#680=DIRECTION('',(0.,0.,-1.));
#681=AXIS2_PLACEMENT_3D('',#678,#679,#680);
#682=CYLINDRICAL_SURFACE('',#681,5.08);
#683=ORIENTED_EDGE('',*,*,#128,.F.);
#684=ORIENTED_EDGE('',*,*,#442,.F.);
#685=ORIENTED_EDGE('',*,*,#356,.F.);
#686=ORIENTED_EDGE('',*,*,#457,.F.);
#687=EDGE_LOOP('',(#683,#684,#685,#686));
#688=FACE_BOUND('',#687,.T.);
#689=ADVANCED_FACE('F499',(#688),#682,.T.);
#690=CARTESIAN_POINT('',(17.145,66.04,-17.145));
#691=DIRECTION('',(0.,-1.,0.));
#692=DIRECTION('',(0.,0.,-1.));
#693=AXIS2_PLACEMENT_3D('',#690,#691,#692);
#694=CYLINDRICAL_SURFACE('',#693,5.08);
#695=ORIENTED_EDGE('',*,*,#194,.F.);
#696=DIRECTION('',(0.,-1.,0.));
#697=VECTOR('',#696,1.);
#698=CARTESIAN_POINT('',(22.2244816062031,66.04,-17.2175714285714));
#699=LINE('',#698,#697);
#700=CARTESIAN_POINT('',(22.2244816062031,26.162,-17.2175714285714));
#701=VERTEX_POINT('',#700);
#702=EDGE_CURVE('E438',#186,#701,#699,.T.);
#703=ORIENTED_EDGE('',*,*,#702,.T.);
#704=CARTESIAN_POINT('',(17.145,26.162,-17.145));
#705=DIRECTION('',(0.,-1.,0.));
#706=DIRECTION('',(0.,0.,-1.));
#707=AXIS2_PLACEMENT_3D('',#704,#705,#706);
#708=CIRCLE('',#707,5.08);
#709=EDGE_CURVE('E435',#701,#382,#708,.T.);
#710=ORIENTED_EDGE('',*,*,#709,.T.);
#711=ORIENTED_EDGE('',*,*,#398,.F.);
#712=ORIENTED_EDGE('',*,*,#324,.F.);
#713=ORIENTED_EDGE('',*,*,#420,.F.);
#714=EDGE_LOOP('',(#695,#703,#710,#711,#712,#713));
#715=FACE_BOUND('',#714,.T.);
#716=ADVANCED_FACE('F536',(#715),#694,.T.);
#717=CARTESIAN_POINT('',(17.145,66.04,17.145));
#718=DIRECTION('',(0.,-1.,0.));
#719=DIRECTION('',(0.,0.,-1.));
#720=AXIS2_PLACEMENT_3D('',#717,#718,#719);
#721=CYLINDRICAL_SURFACE('',#720,5.08);
#722=CARTESIAN_POINT('',(17.145,26.162,17.145));
#723=DIRECTION('',(0.,-1.,0.));
#724=DIRECTION('',(0.,0.,-1.));
#725=AXIS2_PLACEMENT_3D('',#722,#723,#724);
#726=CIRCLE('',#725,5.08);
#727=CARTESIAN_POINT('',(22.2244816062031,26.162,17.2175714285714));
#728=VERTEX_POINT('',#727);
#729=EDGE_CURVE('E424',#384,#728,#726,.T.);
#730=ORIENTED_EDGE('',*,*,#729,.T.);
#731=DIRECTION('',(0.,-1.,0.));
#732=VECTOR('',#731,1.);
#733=CARTESIAN_POINT('',(22.2244816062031,66.04,17.2175714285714));
#734=LINE('',#733,#732);
#735=EDGE_CURVE('E427',#728,#144,#734,.F.);
#736=ORIENTED_EDGE('',*,*,#735,.T.);
#737=ORIENTED_EDGE('',*,*,#145,.F.);
#738=ORIENTED_EDGE('',*,*,#464,.F.);
#739=ORIENTED_EDGE('',*,*,#341,.F.);
#740=ORIENTED_EDGE('',*,*,#391,.F.);
#741=EDGE_LOOP('',(#730,#736,#737,#738,#739,#740));
#742=FACE_BOUND('',#741,.T.);
#743=ADVANCED_FACE('F484',(#742),#721,.T.);
#744=CARTESIAN_POINT('',(22.225,26.162,-13.462));
#745=DIRECTION('',(0.,0.,-1.));
#746=DIRECTION('',(-1.,0.,0.));
#747=AXIS2_PLACEMENT_3D('',#744,#745,#746);
#748=PLANE('',#747);
#749=DIRECTION('',(-1.,0.,0.));
#750=VECTOR('',#749,1.);
#751=CARTESIAN_POINT('',(22.225,26.162,-13.462));
#752=LINE('',#751,#750);
#753=CARTESIAN_POINT('',(26.924,26.162,-13.462));
#754=VERTEX_POINT('',#753);
#755=CARTESIAN_POINT('',(26.0340928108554,26.162,-13.462));
#756=VERTEX_POINT('',#755);
#757=EDGE_CURVE('E339',#754,#756,#752,.T.);
#758=ORIENTED_EDGE('',*,*,#757,.T.);
#759=DIRECTION('',(0.,1.,0.));
#760=VECTOR('',#759,1.);
#761=CARTESIAN_POINT('',(26.0340928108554,66.04,-13.462));
#762=LINE('',#761,#760);
#763=EDGE_CURVE('E432',#756,#177,#762,.T.);
#764=ORIENTED_EDGE('',*,*,#763,.T.);
#765=ORIENTED_EDGE('',*,*,#178,.F.);
#766=DIRECTION('',(0.,1.,0.));
#767=VECTOR('',#766,1.);
#768=CARTESIAN_POINT('',(26.924,26.162,-13.462));
#769=LINE('',#768,#767);
#770=EDGE_CURVE('E350',#754,#169,#769,.T.);
#771=ORIENTED_EDGE('',*,*,#770,.F.);
#772=EDGE_LOOP('',(#758,#764,#765,#771));
#773=FACE_BOUND('',#772,.T.);
#774=ADVANCED_FACE('F480',(#773),#748,.T.);
#775=CARTESIAN_POINT('',(26.924,26.162,-13.462));
#776=DIRECTION('',(1.,0.,0.));
#777=DIRECTION('',(0.,0.,-1.));
#778=AXIS2_PLACEMENT_3D('',#775,#776,#777);
#779=PLANE('',#778);
#780=CARTESIAN_POINT('',(26.924,53.34,0.));
#781=DIRECTION('',(1.,0.,0.));
#782=DIRECTION('',(0.,0.,-1.));
#783=AXIS2_PLACEMENT_3D('',#780,#781,#782);
#784=CIRCLE('',#783,4.96061999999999);
#785=CARTESIAN_POINT('',(26.924,53.34,-4.96061999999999));
#786=VERTEX_POINT('',#785);
#787=EDGE_CURVE('E326',#786,#786,#784,.T.);
#788=ORIENTED_EDGE('',*,*,#787,.F.);
#789=EDGE_LOOP('',(#788));
#790=FACE_BOUND('',#789,.T.);
#791=ORIENTED_EDGE('',*,*,#170,.F.);
#792=DIRECTION('',(0.,1.,0.));
#793=VECTOR('',#792,1.);
#794=CARTESIAN_POINT('',(26.924,26.162,13.462));
#795=LINE('',#794,#793);
#796=CARTESIAN_POINT('',(26.924,26.162,13.462));
#797=VERTEX_POINT('',#796);
#798=EDGE_CURVE('E342',#797,#161,#795,.T.);
#799=ORIENTED_EDGE('',*,*,#798,.F.);
#800=DIRECTION('',(0.,0.,-1.));
#801=VECTOR('',#800,1.);
#802=CARTESIAN_POINT('',(26.924,26.162,-13.462));
#803=LINE('',#802,#801);
#804=EDGE_CURVE('E336',#797,#754,#803,.T.);
#805=ORIENTED_EDGE('',*,*,#804,.T.);
#806=ORIENTED_EDGE('',*,*,#770,.T.);
#807=EDGE_LOOP('',(#791,#799,#805,#806));
#808=FACE_BOUND('',#807,.T.);
#809=ADVANCED_FACE('F483',(#790,#808),#779,.T.);
#810=CARTESIAN_POINT('',(26.924,26.162,13.462));
#811=DIRECTION('',(0.,0.,1.));
#812=DIRECTION('',(1.,0.,0.));
#813=AXIS2_PLACEMENT_3D('',#810,#811,#812);
#814=PLANE('',#813);
#815=ORIENTED_EDGE('',*,*,#162,.F.);
#816=DIRECTION('',(0.,1.,0.));
#817=VECTOR('',#816,1.);
#818=CARTESIAN_POINT('',(26.0340928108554,26.162,13.462));
#819=LINE('',#818,#817);
#820=CARTESIAN_POINT('',(26.0340928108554,26.162,13.462));
#821=VERTEX_POINT('',#820);
#822=EDGE_CURVE('E430',#153,#821,#819,.F.);
#823=ORIENTED_EDGE('',*,*,#822,.T.);
#824=DIRECTION('',(1.,0.,0.));
#825=VECTOR('',#824,1.);
#826=CARTESIAN_POINT('',(26.924,26.162,13.462));
#827=LINE('',#826,#825);
#828=EDGE_CURVE('E333',#821,#797,#827,.T.);
#829=ORIENTED_EDGE('',*,*,#828,.T.);
#830=ORIENTED_EDGE('',*,*,#798,.T.);
#831=EDGE_LOOP('',(#815,#823,#829,#830));
#832=FACE_BOUND('',#831,.T.);
#833=ADVANCED_FACE('F478',(#832),#814,.T.);
#834=CARTESIAN_POINT('',(22.225,26.162,13.462));
#835=DIRECTION('',(0.,-1.,0.));
#836=DIRECTION('',(0.,0.,-1.));
#837=AXIS2_PLACEMENT_3D('',#834,#835,#836);
#838=PLANE('',#837);
#839=ORIENTED_EDGE('',*,*,#385,.F.);
#840=ORIENTED_EDGE('',*,*,#709,.F.);
#841=CARTESIAN_POINT('',(26.0340928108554,26.162,-17.272));
#842=DIRECTION('',(0.,-1.,0.));
#843=DIRECTION('',(0.,0.,-1.));
#844=AXIS2_PLACEMENT_3D('',#841,#842,#843);
#845=CIRCLE('',#844,3.81);
#846=EDGE_CURVE('E447',#701,#756,#845,.F.);
#847=ORIENTED_EDGE('',*,*,#846,.T.);
#848=ORIENTED_EDGE('',*,*,#757,.F.);
#849=ORIENTED_EDGE('',*,*,#804,.F.);
#850=ORIENTED_EDGE('',*,*,#828,.F.);
#851=CARTESIAN_POINT('',(26.0340928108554,26.162,17.272));
#852=DIRECTION('',(0.,-1.,0.));
#853=DIRECTION('',(0.,0.,-1.));
#854=AXIS2_PLACEMENT_3D('',#851,#852,#853);
#855=CIRCLE('',#854,3.81);
#856=EDGE_CURVE('E443',#821,#728,#855,.F.);
#857=ORIENTED_EDGE('',*,*,#856,.T.);
#858=ORIENTED_EDGE('',*,*,#729,.F.);
#859=EDGE_LOOP('',(#839,#840,#847,#848,#849,#850,#857,#858));
#860=FACE_BOUND('',#859,.T.);
#861=ADVANCED_FACE('F474',(#860),#838,.T.);
#862=CARTESIAN_POINT('',(26.0340928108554,66.04,17.272));
#863=DIRECTION('',(0.,-1.,0.));
#864=DIRECTION('',(0.,0.,-1.));
#865=AXIS2_PLACEMENT_3D('',#862,#863,#864);
#866=CYLINDRICAL_SURFACE('',#865,3.81);
#867=ORIENTED_EDGE('',*,*,#856,.F.);
#868=ORIENTED_EDGE('',*,*,#822,.F.);
#869=ORIENTED_EDGE('',*,*,#154,.F.);
#870=ORIENTED_EDGE('',*,*,#735,.F.);
#871=EDGE_LOOP('',(#867,#868,#869,#870));
#872=FACE_BOUND('',#871,.T.);
#873=ADVANCED_FACE('F477',(#872),#866,.F.);
#874=CARTESIAN_POINT('',(26.0340928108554,66.04,-17.272));
#875=DIRECTION('',(0.,-1.,0.));
#876=DIRECTION('',(0.,0.,-1.));
#877=AXIS2_PLACEMENT_3D('',#874,#875,#876);
#878=CYLINDRICAL_SURFACE('',#877,3.81);
#879=ORIENTED_EDGE('',*,*,#846,.F.);
#880=ORIENTED_EDGE('',*,*,#702,.F.);
#881=ORIENTED_EDGE('',*,*,#187,.F.);
#882=ORIENTED_EDGE('',*,*,#763,.F.);
#883=EDGE_LOOP('',(#879,#880,#881,#882));
#884=FACE_BOUND('',#883,.T.);
#885=ADVANCED_FACE('F106',(#884),#878,.F.);
#886=CARTESIAN_POINT('',(0.761999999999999,53.34,0.));
#887=DIRECTION('',(-1.,0.,0.));
#888=DIRECTION('',(0.,0.,1.));
#889=AXIS2_PLACEMENT_3D('',#886,#887,#888);
#890=PLANE('',#889);
#891=CARTESIAN_POINT('',(0.761999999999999,53.34,0.));
#892=DIRECTION('',(1.,0.,0.));
#893=DIRECTION('',(0.,0.,-1.));
#894=AXIS2_PLACEMENT_3D('',#891,#892,#893);
#895=CIRCLE('',#894,4.96061999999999);
#896=EDGE_CURVE('E330',#576,#584,#895,.T.);
#897=ORIENTED_EDGE('',*,*,#896,.T.);
#898=ORIENTED_EDGE('',*,*,#585,.F.);
#899=EDGE_LOOP('',(#897,#898));
#900=FACE_BOUND('',#899,.T.);
#901=ADVANCED_FACE('F469',(#900),#890,.F.);
#902=EDGE_CURVE('E131',#519,#521,#895,.T.);
#903=ORIENTED_EDGE('',*,*,#902,.T.);
#904=ORIENTED_EDGE('',*,*,#522,.F.);
#905=EDGE_LOOP('',(#903,#904));
#906=FACE_BOUND('',#905,.T.);
#907=ADVANCED_FACE('F466',(#906),#890,.F.);
#908=CARTESIAN_POINT('',(26.924,53.34,0.));
#909=DIRECTION('',(1.,0.,0.));
#910=DIRECTION('',(0.,0.,-1.));
#911=AXIS2_PLACEMENT_3D('',#908,#909,#910);
#912=CYLINDRICAL_SURFACE('',#911,4.96061999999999);
#913=ORIENTED_EDGE('',*,*,#787,.T.);
#914=EDGE_LOOP('',(#913));
#915=FACE_BOUND('',#914,.T.);
#916=ORIENTED_EDGE('',*,*,#902,.F.);
#917=ORIENTED_EDGE('',*,*,#638,.F.);
#918=ORIENTED_EDGE('',*,*,#896,.F.);
#919=ORIENTED_EDGE('',*,*,#577,.F.);
#920=EDGE_LOOP('',(#916,#917,#918,#919));
#921=FACE_BOUND('',#920,.T.);
#922=ADVANCED_FACE('F460',(#915,#921),#912,.F.);
#923=CARTESIAN_POINT('',(16.8402,66.04,16.8402));
#924=DIRECTION('',(0.,1.,0.));
#925=DIRECTION('',(0.,0.,1.));
#926=AXIS2_PLACEMENT_3D('',#923,#924,#925);
#927=CYLINDRICAL_SURFACE('',#926,1.89864999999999);
#928=ORIENTED_EDGE('',*,*,#367,.F.);
#929=EDGE_LOOP('',(#928));
#930=FACE_BOUND('',#929,.T.);
#931=ORIENTED_EDGE('',*,*,#216,.T.);
#932=EDGE_LOOP('',(#931));
#933=FACE_BOUND('',#932,.T.);
#934=ADVANCED_FACE('F465',(#930,#933),#927,.F.);
#935=CARTESIAN_POINT('',(-16.8402,66.04,-16.8402));
#936=DIRECTION('',(0.,1.,0.));
#937=DIRECTION('',(0.,0.,1.));
#938=AXIS2_PLACEMENT_3D('',#935,#936,#937);
#939=CYLINDRICAL_SURFACE('',#938,1.89864999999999);
#940=ORIENTED_EDGE('',*,*,#286,.F.);
#941=EDGE_LOOP('',(#940));
#942=FACE_BOUND('',#941,.T.);
#943=ORIENTED_EDGE('',*,*,#90,.T.);
#944=EDGE_LOOP('',(#943));
#945=FACE_BOUND('',#944,.T.);
#946=ADVANCED_FACE('F592',(#942,#945),#939,.F.);
#947=CARTESIAN_POINT('',(-16.8402,66.04,16.8402));
#948=DIRECTION('',(0.,1.,0.));
#949=DIRECTION('',(0.,0.,1.));
#950=AXIS2_PLACEMENT_3D('',#947,#948,#949);
#951=CYLINDRICAL_SURFACE('',#950,2.70509999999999);
#952=ORIENTED_EDGE('',*,*,#275,.F.);
#953=EDGE_LOOP('',(#952));
#954=FACE_BOUND('',#953,.T.);
#955=ORIENTED_EDGE('',*,*,#227,.T.);
#956=EDGE_LOOP('',(#955));
#957=FACE_BOUND('',#956,.T.);
#958=ADVANCED_FACE('F598',(#954,#957),#951,.F.);
#959=CARTESIAN_POINT('',(16.8402,66.04,-16.8402));
#960=DIRECTION('',(0.,1.,0.));
#961=DIRECTION('',(0.,0.,1.));
#962=AXIS2_PLACEMENT_3D('',#959,#960,#961);
#963=CYLINDRICAL_SURFACE('',#962,2.70509999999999);
#964=ORIENTED_EDGE('',*,*,#264,.F.);
#965=EDGE_LOOP('',(#964));
#966=FACE_BOUND('',#965,.T.);
#967=ORIENTED_EDGE('',*,*,#79,.T.);
#968=EDGE_LOOP('',(#967));
#969=FACE_BOUND('',#968,.T.);
#970=ADVANCED_FACE('F600',(#966,#969),#963,.F.);
#971=CARTESIAN_POINT('',(0.,0.,9.52500000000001));
#972=DIRECTION('',(0.,-1.,0.));
#973=DIRECTION('',(0.,0.,-1.));
#974=AXIS2_PLACEMENT_3D('',#971,#972,#973);
#975=CYLINDRICAL_SURFACE('',#974,10.5);
#976=CARTESIAN_POINT('',(0.,0.253999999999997,9.52500000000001));
#977=DIRECTION('',(0.,-1.,0.));
#978=DIRECTION('',(0.,0.,-1.));
#979=AXIS2_PLACEMENT_3D('',#976,#977,#978);
#980=CIRCLE('',#979,10.5);
#981=CARTESIAN_POINT('',(4.41863949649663,0.253999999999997,0.));
#982=VERTEX_POINT('',#981);
#983=CARTESIAN_POINT('',(-4.41863949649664,0.253999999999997,0.));
#984=VERTEX_POINT('',#983);
#985=EDGE_CURVE('E297',#982,#984,#980,.T.);
#986=ORIENTED_EDGE('',*,*,#985,.F.);
#987=DIRECTION('',(0.,-1.,0.));
#988=VECTOR('',#987,1.);
#989=CARTESIAN_POINT('',(4.41863949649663,0.126999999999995,0.));
#990=LINE('',#989,#988);
#991=EDGE_CURVE('E273',#982,#245,#990,.T.);
#992=ORIENTED_EDGE('',*,*,#991,.T.);
#993=ORIENTED_EDGE('',*,*,#253,.T.);
#994=DIRECTION('',(0.,-1.,0.));
#995=VECTOR('',#994,1.);
#996=CARTESIAN_POINT('',(-4.41863949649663,0.126999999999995,0.));
#997=LINE('',#996,#995);
#998=EDGE_CURVE('E270',#243,#984,#997,.F.);
#999=ORIENTED_EDGE('',*,*,#998,.T.);
#1000=EDGE_LOOP('',(#986,#992,#993,#999));
#1001=FACE_BOUND('',#1000,.T.);
#1002=ADVANCED_FACE('F607',(#1001),#975,.F.);
#1003=CARTESIAN_POINT('',(-6.22500000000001,0.253999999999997,9.52500000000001));
#1004=DIRECTION('',(0.,1.,0.));
#1005=DIRECTION('',(0.,0.,1.));
#1006=AXIS2_PLACEMENT_3D('',#1003,#1004,#1005);
#1007=PLANE('',#1006);
#1008=CARTESIAN_POINT('',(0.,0.253999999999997,9.52500000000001));
#1009=DIRECTION('',(0.,-1.,0.));
#1010=DIRECTION('',(0.,0.,-1.));
#1011=AXIS2_PLACEMENT_3D('',#1008,#1009,#1010);
#1012=CIRCLE('',#1011,6.225);
#1013=CARTESIAN_POINT('',(0.,0.253999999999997,3.3));
#1014=VERTEX_POINT('',#1013);
#1015=EDGE_CURVE('E294',#1014,#1014,#1012,.T.);
#1016=ORIENTED_EDGE('',*,*,#1015,.F.);
#1017=EDGE_LOOP('',(#1016));
#1018=FACE_BOUND('',#1017,.T.);
#1019=ORIENTED_EDGE('',*,*,#985,.T.);
#1020=CARTESIAN_POINT('',(0.,0.253999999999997,-9.52500000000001));
#1021=DIRECTION('',(0.,-1.,0.));
#1022=DIRECTION('',(0.,0.,-1.));
#1023=AXIS2_PLACEMENT_3D('',#1020,#1021,#1022);
#1024=CIRCLE('',#1023,10.5);
#1025=EDGE_CURVE('E123',#984,#982,#1024,.T.);
#1026=ORIENTED_EDGE('',*,*,#1025,.T.);
#1027=EDGE_LOOP('',(#1019,#1026));
#1028=FACE_BOUND('',#1027,.T.);
#1029=CARTESIAN_POINT('',(0.,0.253999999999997,-9.52500000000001));
#1030=DIRECTION('',(0.,-1.,0.));
#1031=DIRECTION('',(0.,0.,-1.));
#1032=AXIS2_PLACEMENT_3D('',#1029,#1030,#1031);
#1033=CIRCLE('',#1032,6.225);
#1034=CARTESIAN_POINT('',(0.,0.253999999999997,-15.75));
#1035=VERTEX_POINT('',#1034);
#1036=EDGE_CURVE('E264',#1035,#1035,#1033,.T.);
#1037=ORIENTED_EDGE('',*,*,#1036,.F.);
#1038=EDGE_LOOP('',(#1037));
#1039=FACE_BOUND('',#1038,.T.);
#1040=ADVANCED_FACE('F615',(#1018,#1028,#1039),#1007,.F.);
#1041=CARTESIAN_POINT('',(0.,0.508000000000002,9.52500000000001));
#1042=DIRECTION('',(0.,-1.,0.));
#1043=DIRECTION('',(0.,0.,-1.));
#1044=AXIS2_PLACEMENT_3D('',#1041,#1042,#1043);
#1045=TOROIDAL_SURFACE('',#1044,6.225,0.254000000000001);
#1046=CARTESIAN_POINT('',(0.,0.455190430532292,9.52500000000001));
#1047=DIRECTION('',(0.,-1.,0.));
#1048=DIRECTION('',(0.,0.,-1.));
#1049=AXIS2_PLACEMENT_3D('',#1046,#1047,#1048);
#1050=CIRCLE('',#1049,5.97655050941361);
#1051=CARTESIAN_POINT('',(0.,0.455190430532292,3.54844949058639));
#1052=VERTEX_POINT('',#1051);
#1053=EDGE_CURVE('E291',#1052,#1052,#1050,.T.);
#1054=ORIENTED_EDGE('',*,*,#1053,.F.);
#1055=EDGE_LOOP('',(#1054));
#1056=FACE_BOUND('',#1055,.T.);
#1057=ORIENTED_EDGE('',*,*,#1015,.T.);
#1058=EDGE_LOOP('',(#1057));
#1059=FACE_BOUND('',#1058,.T.);
#1060=ADVANCED_FACE('F619',(#1056,#1059),#1045,.T.);
#1061=CARTESIAN_POINT('',(0.,0.455190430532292,9.52500000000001));
#1062=DIRECTION('',(0.,-1.,0.));
#1063=DIRECTION('',(0.,0.,-1.));
#1064=AXIS2_PLACEMENT_3D('',#1061,#1062,#1063);
#1065=CONICAL_SURFACE('',#1064,5.97655050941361,0.209439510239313);
#1066=CARTESIAN_POINT('',(0.,2.854,9.52500000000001));
#1067=DIRECTION('',(0.,-1.,0.));
#1068=DIRECTION('',(0.,0.,-1.));
#1069=AXIS2_PLACEMENT_3D('',#1066,#1067,#1068);
#1070=CIRCLE('',#1069,5.46666779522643);
#1071=CARTESIAN_POINT('',(0.,2.854,4.05833220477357));
#1072=VERTEX_POINT('',#1071);
#1073=EDGE_CURVE('E288',#1072,#1072,#1070,.T.);
#1074=ORIENTED_EDGE('',*,*,#1073,.F.);
#1075=EDGE_LOOP('',(#1074));
#1076=FACE_BOUND('',#1075,.T.);
#1077=ORIENTED_EDGE('',*,*,#1053,.T.);
#1078=EDGE_LOOP('',(#1077));
#1079=FACE_BOUND('',#1078,.T.);
#1080=ADVANCED_FACE('F623',(#1076,#1079),#1065,.F.);
#1081=CARTESIAN_POINT('',(0.,2.854,9.52500000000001));
#1082=DIRECTION('',(0.,-1.,0.));
#1083=DIRECTION('',(0.,0.,-1.));
#1084=AXIS2_PLACEMENT_3D('',#1081,#1082,#1083);
#1085=CONICAL_SURFACE('',#1084,5.46666779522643,0.785398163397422);
#1086=CARTESIAN_POINT('',(0.,2.76441779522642,9.52500000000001));
#1087=DIRECTION('',(0.,-1.,0.));
#1088=DIRECTION('',(0.,0.,-1.));
#1089=AXIS2_PLACEMENT_3D('',#1086,#1087,#1088);
#1090=CIRCLE('',#1089,5.55625);
#1091=CARTESIAN_POINT('',(0.,2.76441779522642,3.96875));
#1092=VERTEX_POINT('',#1091);
#1093=EDGE_CURVE('E285',#1092,#1092,#1090,.T.);
#1094=ORIENTED_EDGE('',*,*,#1093,.F.);
#1095=EDGE_LOOP('',(#1094));
#1096=FACE_BOUND('',#1095,.T.);
#1097=ORIENTED_EDGE('',*,*,#1073,.T.);
#1098=EDGE_LOOP('',(#1097));
#1099=FACE_BOUND('',#1098,.T.);
#1100=ADVANCED_FACE('F627',(#1096,#1099),#1085,.T.);
#1101=CARTESIAN_POINT('',(0.,0.,9.52500000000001));
#1102=DIRECTION('',(0.,-1.,0.));
#1103=DIRECTION('',(0.,0.,-1.));
#1104=AXIS2_PLACEMENT_3D('',#1101,#1102,#1103);
#1105=CYLINDRICAL_SURFACE('',#1104,5.55625);
#1106=CARTESIAN_POINT('',(0.,11.754,9.52500000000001));
#1107=DIRECTION('',(0.,-1.,0.));
#1108=DIRECTION('',(0.,0.,-1.));
#1109=AXIS2_PLACEMENT_3D('',#1106,#1107,#1108);
#1110=CIRCLE('',#1109,5.55625);
#1111=CARTESIAN_POINT('',(0.,11.754,3.96875));
#1112=VERTEX_POINT('',#1111);
#1113=EDGE_CURVE('E282',#1112,#1112,#1110,.T.);
#1114=ORIENTED_EDGE('',*,*,#1113,.F.);
#1115=EDGE_LOOP('',(#1114));
#1116=FACE_BOUND('',#1115,.T.);
#1117=ORIENTED_EDGE('',*,*,#1093,.T.);
#1118=EDGE_LOOP('',(#1117));
#1119=FACE_BOUND('',#1118,.T.);
#1120=ADVANCED_FACE('F631',(#1116,#1119),#1105,.F.);
#1121=CARTESIAN_POINT('',(-4.96062,11.754,9.52500000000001));
#1122=DIRECTION('',(0.,1.,0.));
#1123=DIRECTION('',(0.,0.,1.));
#1124=AXIS2_PLACEMENT_3D('',#1121,#1122,#1123);
#1125=PLANE('',#1124);
#1126=CARTESIAN_POINT('',(0.,11.754,9.52500000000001));
#1127=DIRECTION('',(0.,-1.,0.));
#1128=DIRECTION('',(0.,0.,-1.));
#1129=AXIS2_PLACEMENT_3D('',#1126,#1127,#1128);
#1130=CIRCLE('',#1129,4.96062);
#1131=CARTESIAN_POINT('',(0.,11.754,4.56438));
#1132=VERTEX_POINT('',#1131);
#1133=EDGE_CURVE('E279',#1132,#1132,#1130,.T.);
#1134=ORIENTED_EDGE('',*,*,#1133,.F.);
#1135=EDGE_LOOP('',(#1134));
#1136=FACE_BOUND('',#1135,.T.);
#1137=ORIENTED_EDGE('',*,*,#1113,.T.);
#1138=EDGE_LOOP('',(#1137));
#1139=FACE_BOUND('',#1138,.T.);
#1140=ADVANCED_FACE('F635',(#1136,#1139),#1125,.F.);
#1141=CARTESIAN_POINT('',(0.,0.,9.52500000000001));
#1142=DIRECTION('',(0.,-1.,0.));
#1143=DIRECTION('',(0.,0.,-1.));
#1144=AXIS2_PLACEMENT_3D('',#1141,#1142,#1143);
#1145=CYLINDRICAL_SURFACE('',#1144,4.96062);
#1146=CARTESIAN_POINT('',(0.,14.254,9.52500000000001));
#1147=DIRECTION('',(0.,-1.,0.));
#1148=DIRECTION('',(0.,0.,-1.));
#1149=AXIS2_PLACEMENT_3D('',#1146,#1147,#1148);
#1150=CIRCLE('',#1149,4.96062);
#1151=CARTESIAN_POINT('',(0.,14.254,4.56438));
#1152=VERTEX_POINT('',#1151);
#1153=EDGE_CURVE('E276',#1152,#1152,#1150,.T.);
#1154=ORIENTED_EDGE('',*,*,#1153,.F.);
#1155=EDGE_LOOP('',(#1154));
#1156=FACE_BOUND('',#1155,.T.);
#1157=ORIENTED_EDGE('',*,*,#1133,.T.);
#1158=EDGE_LOOP('',(#1157));
#1159=FACE_BOUND('',#1158,.T.);
#1160=ADVANCED_FACE('F639',(#1156,#1159),#1145,.F.);
#1161=CARTESIAN_POINT('',(0.,14.254,9.52500000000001));
#1162=DIRECTION('',(0.,-1.,0.));
#1163=DIRECTION('',(0.,0.,-1.));
#1164=AXIS2_PLACEMENT_3D('',#1161,#1162,#1163);
#1165=CONICAL_SURFACE('',#1164,4.96062,1.02974425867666);
#1166=CARTESIAN_POINT('',(0.,17.2346412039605,9.52500000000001));
#1167=VERTEX_POINT('',#1166);
#1168=VERTEX_LOOP('',#1167);
#1169=FACE_BOUND('',#1168,.T.);
#1170=ORIENTED_EDGE('',*,*,#1153,.T.);
#1171=EDGE_LOOP('',(#1170));
#1172=FACE_BOUND('',#1171,.T.);
#1173=ADVANCED_FACE('F643',(#1169,#1172),#1165,.F.);
#1174=CARTESIAN_POINT('',(0.,0.,-9.52500000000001));
#1175=DIRECTION('',(0.,-1.,0.));
#1176=DIRECTION('',(0.,0.,-1.));
#1177=AXIS2_PLACEMENT_3D('',#1174,#1175,#1176);
#1178=CYLINDRICAL_SURFACE('',#1177,10.5);
#1179=ORIENTED_EDGE('',*,*,#1025,.F.);
#1180=ORIENTED_EDGE('',*,*,#998,.F.);
#1181=ORIENTED_EDGE('',*,*,#246,.T.);
#1182=ORIENTED_EDGE('',*,*,#991,.F.);
#1183=EDGE_LOOP('',(#1179,#1180,#1181,#1182));
#1184=FACE_BOUND('',#1183,.T.);
#1185=ADVANCED_FACE('F647',(#1184),#1178,.F.);
#1186=CARTESIAN_POINT('',(0.,0.508000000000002,-9.52500000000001));
#1187=DIRECTION('',(0.,-1.,0.));
#1188=DIRECTION('',(0.,0.,-1.));
#1189=AXIS2_PLACEMENT_3D('',#1186,#1187,#1188);
#1190=TOROIDAL_SURFACE('',#1189,6.225,0.254000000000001);
#1191=CARTESIAN_POINT('',(0.,0.455190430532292,-9.52500000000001));
#1192=DIRECTION('',(0.,-1.,0.));
#1193=DIRECTION('',(0.,0.,-1.));
#1194=AXIS2_PLACEMENT_3D('',#1191,#1192,#1193);
#1195=CIRCLE('',#1194,5.97655050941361);
#1196=CARTESIAN_POINT('',(0.,0.455190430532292,-15.5015505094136));
#1197=VERTEX_POINT('',#1196);
#1198=EDGE_CURVE('E261',#1197,#1197,#1195,.T.);
#1199=ORIENTED_EDGE('',*,*,#1198,.F.);
#1200=EDGE_LOOP('',(#1199));
#1201=FACE_BOUND('',#1200,.T.);
#1202=ORIENTED_EDGE('',*,*,#1036,.T.);
#1203=EDGE_LOOP('',(#1202));
#1204=FACE_BOUND('',#1203,.T.);
#1205=ADVANCED_FACE('F651',(#1201,#1204),#1190,.T.);
#1206=CARTESIAN_POINT('',(0.,0.455190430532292,-9.52500000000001));
#1207=DIRECTION('',(0.,-1.,0.));
#1208=DIRECTION('',(0.,0.,-1.));
#1209=AXIS2_PLACEMENT_3D('',#1206,#1207,#1208);
#1210=CONICAL_SURFACE('',#1209,5.97655050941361,0.209439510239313);
#1211=CARTESIAN_POINT('',(0.,2.854,-9.52500000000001));
#1212=DIRECTION('',(0.,-1.,0.));
#1213=DIRECTION('',(0.,0.,-1.));
#1214=AXIS2_PLACEMENT_3D('',#1211,#1212,#1213);
#1215=CIRCLE('',#1214,5.46666779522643);
#1216=CARTESIAN_POINT('',(0.,2.854,-14.9916677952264));
#1217=VERTEX_POINT('',#1216);
#1218=EDGE_CURVE('E258',#1217,#1217,#1215,.T.);
#1219=ORIENTED_EDGE('',*,*,#1218,.F.);
#1220=EDGE_LOOP('',(#1219));
#1221=FACE_BOUND('',#1220,.T.);
#1222=ORIENTED_EDGE('',*,*,#1198,.T.);
#1223=EDGE_LOOP('',(#1222));
#1224=FACE_BOUND('',#1223,.T.);
#1225=ADVANCED_FACE('F655',(#1221,#1224),#1210,.F.);
#1226=CARTESIAN_POINT('',(0.,2.854,-9.52500000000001));
#1227=DIRECTION('',(0.,-1.,0.));
#1228=DIRECTION('',(0.,0.,-1.));
#1229=AXIS2_PLACEMENT_3D('',#1226,#1227,#1228);
#1230=CONICAL_SURFACE('',#1229,5.46666779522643,0.785398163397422);
#1231=CARTESIAN_POINT('',(0.,2.76441779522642,-9.52500000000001));
#1232=DIRECTION('',(0.,-1.,0.));
#1233=DIRECTION('',(0.,0.,-1.));
#1234=AXIS2_PLACEMENT_3D('',#1231,#1232,#1233);
#1235=CIRCLE('',#1234,5.55625);
#1236=CARTESIAN_POINT('',(0.,2.76441779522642,-15.08125));
#1237=VERTEX_POINT('',#1236);
#1238=EDGE_CURVE('E255',#1237,#1237,#1235,.T.);
#1239=ORIENTED_EDGE('',*,*,#1238,.F.);
#1240=EDGE_LOOP('',(#1239));
#1241=FACE_BOUND('',#1240,.T.);
#1242=ORIENTED_EDGE('',*,*,#1218,.T.);
#1243=EDGE_LOOP('',(#1242));
#1244=FACE_BOUND('',#1243,.T.);
#1245=ADVANCED_FACE('F659',(#1241,#1244),#1230,.T.);
#1246=CARTESIAN_POINT('',(0.,0.,-9.52500000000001));
#1247=DIRECTION('',(0.,-1.,0.));
#1248=DIRECTION('',(0.,0.,-1.));
#1249=AXIS2_PLACEMENT_3D('',#1246,#1247,#1248);
#1250=CYLINDRICAL_SURFACE('',#1249,5.55625);
#1251=CARTESIAN_POINT('',(0.,11.754,-9.52500000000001));
#1252=DIRECTION('',(0.,-1.,0.));
#1253=DIRECTION('',(0.,0.,-1.));
#1254=AXIS2_PLACEMENT_3D('',#1251,#1252,#1253);
#1255=CIRCLE('',#1254,5.55625);
#1256=CARTESIAN_POINT('',(0.,11.754,-15.08125));
#1257=VERTEX_POINT('',#1256);
#1258=EDGE_CURVE('E250',#1257,#1257,#1255,.T.);
#1259=ORIENTED_EDGE('',*,*,#1258,.F.);
#1260=EDGE_LOOP('',(#1259));
#1261=FACE_BOUND('',#1260,.T.);
#1262=ORIENTED_EDGE('',*,*,#1238,.T.);
#1263=EDGE_LOOP('',(#1262));
#1264=FACE_BOUND('',#1263,.T.);
#1265=ADVANCED_FACE('F663',(#1261,#1264),#1250,.F.);
#1266=CARTESIAN_POINT('',(-4.96062,11.754,-9.52500000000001));
#1267=DIRECTION('',(0.,1.,0.));
#1268=DIRECTION('',(0.,0.,1.));
#1269=AXIS2_PLACEMENT_3D('',#1266,#1267,#1268);
#1270=PLANE('',#1269);
#1271=CARTESIAN_POINT('',(0.,11.754,-9.52500000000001));
#1272=DIRECTION('',(0.,-1.,0.));
#1273=DIRECTION('',(0.,0.,-1.));
#1274=AXIS2_PLACEMENT_3D('',#1271,#1272,#1273);
#1275=CIRCLE('',#1274,4.96062);
#1276=CARTESIAN_POINT('',(0.,11.754,-14.48562));
#1277=VERTEX_POINT('',#1276);
#1278=EDGE_CURVE('E247',#1277,#1277,#1275,.T.);
#1279=ORIENTED_EDGE('',*,*,#1278,.F.);
#1280=EDGE_LOOP('',(#1279));
#1281=FACE_BOUND('',#1280,.T.);
#1282=ORIENTED_EDGE('',*,*,#1258,.T.);
#1283=EDGE_LOOP('',(#1282));
#1284=FACE_BOUND('',#1283,.T.);
#1285=ADVANCED_FACE('F667',(#1281,#1284),#1270,.F.);
#1286=CARTESIAN_POINT('',(0.,0.,-9.52500000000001));
#1287=DIRECTION('',(0.,-1.,0.));
#1288=DIRECTION('',(0.,0.,-1.));
#1289=AXIS2_PLACEMENT_3D('',#1286,#1287,#1288);
#1290=CYLINDRICAL_SURFACE('',#1289,4.96062);
#1291=CARTESIAN_POINT('',(0.,14.254,-9.52500000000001));
#1292=DIRECTION('',(0.,-1.,0.));
#1293=DIRECTION('',(0.,0.,-1.));
#1294=AXIS2_PLACEMENT_3D('',#1291,#1292,#1293);
#1295=CIRCLE('',#1294,4.96062);
#1296=CARTESIAN_POINT('',(0.,14.254,-14.48562));
#1297=VERTEX_POINT('',#1296);
#1298=EDGE_CURVE('E245',#1297,#1297,#1295,.T.);
#1299=ORIENTED_EDGE('',*,*,#1298,.F.);
#1300=EDGE_LOOP('',(#1299));
#1301=FACE_BOUND('',#1300,.T.);
#1302=ORIENTED_EDGE('',*,*,#1278,.T.);
#1303=EDGE_LOOP('',(#1302));
#1304=FACE_BOUND('',#1303,.T.);
#1305=ADVANCED_FACE('F241',(#1301,#1304),#1290,.F.);
#1306=CARTESIAN_POINT('',(0.,14.254,-9.52500000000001));
#1307=DIRECTION('',(0.,-1.,0.));
#1308=DIRECTION('',(0.,0.,-1.));
#1309=AXIS2_PLACEMENT_3D('',#1306,#1307,#1308);
#1310=CONICAL_SURFACE('',#1309,4.96062,1.02974425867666);
#1311=CARTESIAN_POINT('',(0.,17.2346412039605,-9.52500000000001));
#1312=VERTEX_POINT('',#1311);
#1313=VERTEX_LOOP('',#1312);
#1314=FACE_BOUND('',#1313,.T.);
#1315=ORIENTED_EDGE('',*,*,#1298,.T.);
#1316=EDGE_LOOP('',(#1315));
#1317=FACE_BOUND('',#1316,.T.);
#1318=ADVANCED_FACE('F238',(#1314,#1317),#1310,.F.);
#1319=CLOSED_SHELL('',(#231,#371,#402,#424,#446,#468,#488,#508,#656,#665,#677,#689,#716,#743,
#774,#809,#833,#861,#873,#885,#901,#907,#922,#934,#946,#958,#970,#1002,#1040,#1060,#1080,#1100,
#1120,#1140,#1160,#1173,#1185,#1205,#1225,#1245,#1265,#1285,#1305,#1318));
#1320=MANIFOLD_SOLID_BREP('B8',#1319);
#1321=ADVANCED_BREP_SHAPE_REPRESENTATION('',(#18,#66,#1320),#14);
#1322=SHAPE_DEFINITION_REPRESENTATION(#9,#1321);
ENDSEC;
END-ISO-10303-21;
